VERSION 5.4 ;
NAMESCASESENSITIVE ON ;

UNITS
    DATABASE MICRONS 100 ;
END UNITS

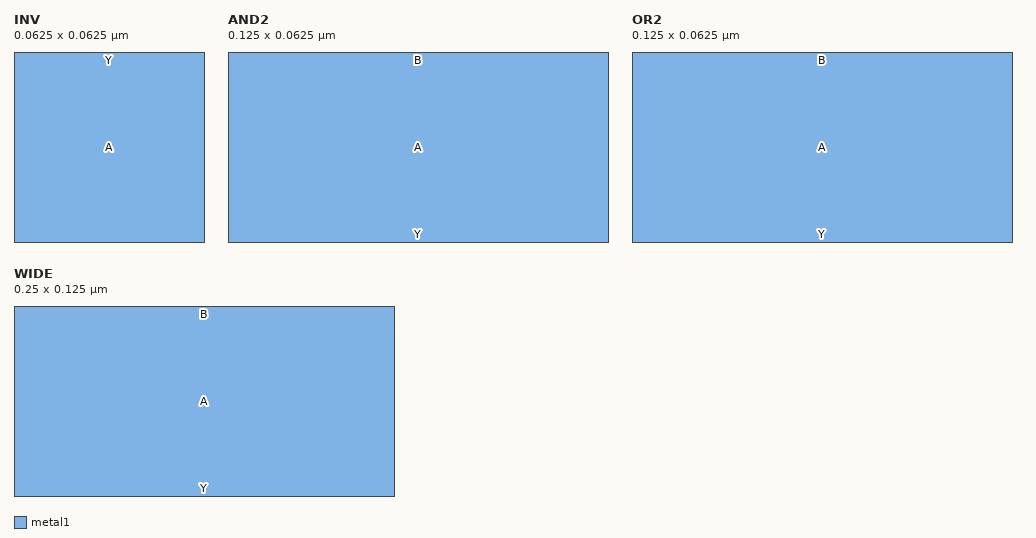
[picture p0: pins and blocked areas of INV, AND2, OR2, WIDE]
MACRO INV
    CLASS CORE ;
    ORIGIN 0.000 0.000 ;
    SIZE 0.0625 BY 0.0625 ;
    SYMMETRY x y ;
    PIN Y
        DIRECTION OUTPUT ;
        PORT
        LAYER metal1 ;
        RECT 0.0 0.0 0.0625 0.0625 ;
        END
    END Y
    PIN A
        DIRECTION INPUT ;
        PORT
        LAYER metal1 ;
        RECT 0.0 0.0 0.0625 0.0625 ;
        END
    END A
END INV

MACRO AND2
    CLASS CORE ;
    ORIGIN 0.000 0.000 ;
    SIZE 0.125 BY 0.0625 ;
    SYMMETRY x y ;
    PIN Y
        DIRECTION OUTPUT ;
        PORT
        LAYER metal1 ;
        RECT 0.0 0.0 0.125 0.0625 ;
        END
    END Y
    PIN A
        DIRECTION INPUT ;
        PORT
        LAYER metal1 ;
        RECT 0.0 0.0 0.125 0.0625 ;
        END
    END A
    PIN B
        DIRECTION INPUT ;
        PORT
        LAYER metal1 ;
        RECT 0.0 0.0 0.125 0.0625 ;
        END
    END B
END AND2

MACRO OR2
    CLASS CORE ;
    ORIGIN 0.000 0.000 ;
    SIZE 0.125 BY 0.0625 ;
    SYMMETRY x y ;
    PIN Y
        DIRECTION OUTPUT ;
        PORT
        LAYER metal1 ;
        RECT 0.0 0.0 0.125 0.0625 ;
        END
    END Y
    PIN A
        DIRECTION INPUT ;
        PORT
        LAYER metal1 ;
        RECT 0.0 0.0 0.125 0.0625 ;
        END
    END A
    PIN B
        DIRECTION INPUT ;
        PORT
        LAYER metal1 ;
        RECT 0.0 0.0 0.125 0.0625 ;
        END
    END B
END OR2

MACRO WIDE
    CLASS CORE ;
    ORIGIN 0.000 0.000 ;
    SIZE 0.25 BY 0.125 ;
    SYMMETRY x y ;
    PIN Y
        DIRECTION OUTPUT ;
        PORT
        LAYER metal1 ;
        RECT 0.0 0.0 0.25 0.125 ;
        END
    END Y
    PIN A
        DIRECTION INPUT ;
        PORT
        LAYER metal1 ;
        RECT 0.0 0.0 0.25 0.125 ;
        END
    END A
    PIN B
        DIRECTION INPUT ;
        PORT
        LAYER metal1 ;
        RECT 0.0 0.0 0.25 0.125 ;
        END
    END B
END WIDE

END LIBRARY
